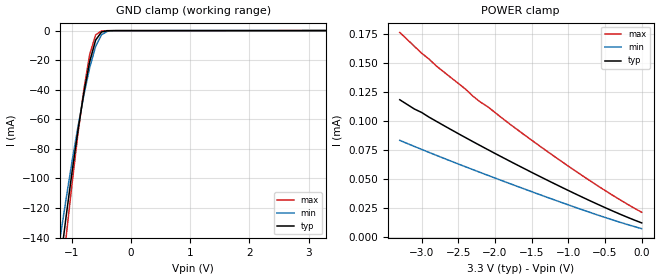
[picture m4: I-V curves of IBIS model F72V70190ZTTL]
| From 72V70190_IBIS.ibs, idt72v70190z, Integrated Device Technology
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|   Model F72V70190ZTTL
[Model]   F72V70190ZTTL
Model_type   Input
Vinl =  0.000V
Vinh =  3.000V
Vmeas =  1.500V
C_comp   3.00pF   NA   NA
[Temperature Range]   25.00   85.00   -40.00
[Voltage Range]   3.30V   3.00V   3.60V
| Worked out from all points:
|   GND clamp passes 1 mA (typ) near -0.50 V on its own axis
[GND_clamp]
| voltage   I(typ)   I(min)   I(max)
-3.3V     -959mA     -827mA     -1.095A
-1.2V     -158mA     -140mA     -179mA
-1.1V     -126mA     -114mA     -140mA
-1V       -95.96mA   -88.79mA   -104mA
-900mV    -67.8mA    -65.3mA    -70.17mA
-800mV    -42.35mA   -43.76mA   -40.1mA
-700mV    -20.92mA   -24.96mA   -16.07mA
-600mV    -6.411mA   -10.62mA   -2.873mA
-500mV    -933uA     -2.8mA     -215uA
-400mV    -103uA     -456uA     -51.61uA
-300mV    -32.77uA   -71.01uA   -44.13uA
3.3V      11.95uA    12.59uA    11.51uA
[POWER_clamp]
| voltage   I(typ)   I(min)   I(max)
-3.3V     118uA      83.05uA    176uA
-3.1V     110uA      77.79uA    164uA
-3V       107uA      75.21uA    158uA
-2.8V     99.41uA    70.12uA    147uA
-2.4V     85.3uA     60.21uA    127uA
-2.2V     78.46uA    55.36uA    116uA
-2.1V     75.09uA    52.96uA    112uA
-1.7V     61.9uA     43.49uA    92.44uA
-1.2V     46.01uA    31.96uA    69.6uA
-700mV    30.88uA    20.88uA    48.05uA
-300mV    19.61uA    12.59uA    32.03uA
0V        11.95uA    6.989uA    21.11uA
